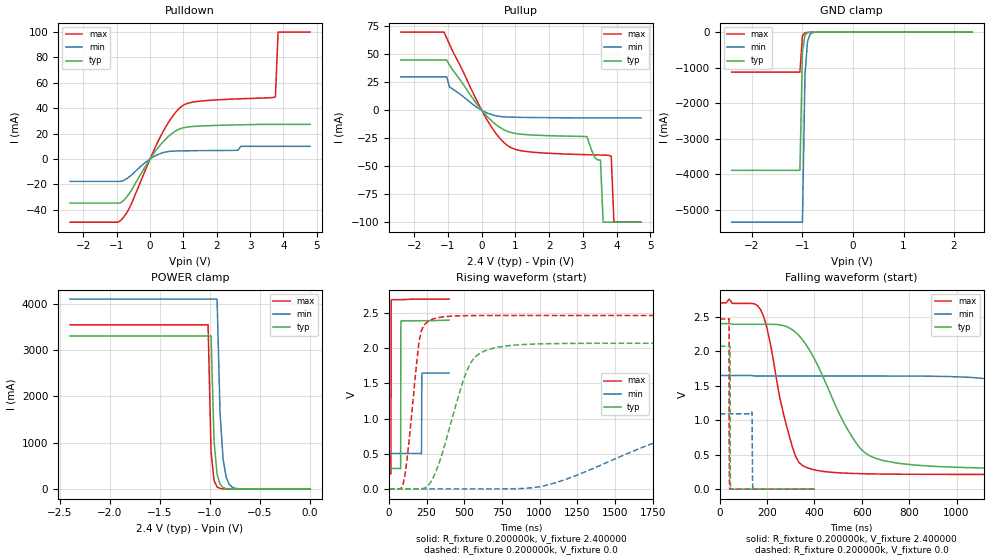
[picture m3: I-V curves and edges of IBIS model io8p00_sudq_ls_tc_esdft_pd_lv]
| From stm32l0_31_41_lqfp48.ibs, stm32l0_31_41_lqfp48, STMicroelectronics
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|   Model io8p00_sudq_ls_tc_esdft_pd_lv
[Model]  io8p00_sudq_ls_tc_esdft_pd_lv
Model_type I/O
Polarity   Non-Inverting
Enable   Active-Low
Vinl =   0.720000V
Vinh =   1.680000V
Vmeas =  1.200000V
Cref =   50.000000pF
Rref =   100.000000M
Vref =   0.0V
C_comp   2.242700pF   2.201100pF   2.288600pF
[Temperature Range]   25.000000   0.105000k   -40.000000
[Pullup Reference]   2.400000V   1.650000V   2.700000V
[Pulldown Reference]   0.0V   0.0V   0.0V
[POWER Clamp Reference]   2.400000V   1.650000V   2.700000V
[GND Clamp Reference]   0.0V   0.0V   0.0V
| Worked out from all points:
|   slope of the pulldown table from 0 to 0.36 V, typ, clamps not added: 28.4 ohm
|   slope of the pullup table from 0 to 0.36 V, typ, clamps not added: 32.2 ohm
|   GND clamp passes 1 mA (typ) near -0.64 V on its own axis
|   POWER clamp passes 1 mA (typ) near -0.63 V on its own axis
|   rising waveform, R_fixture 0.200000k, V_fixture 2.400000: 20-80 % time 636ps typ, 853ps min, 665ps max; typ from 0.29 V to 2.4 V
|   rising waveform, R_fixture 0.200000k, V_fixture 0.0: 20-80 % time 173ns typ, 835ns min, 69.6ns max; typ from 0 V to 2.07 V
|   falling waveform, R_fixture 0.200000k, V_fixture 2.400000: 20-80 % time 182ns typ, 740ns min, 90.7ns max; typ from 2.4 V to 0.29 V
|   falling waveform, R_fixture 0.200000k, V_fixture 0.0: 20-80 % time 751ps typ, 1.17ns min, 663ps max; typ from 2.07 V to 0 V
[Pulldown]
|Voltage   I(typ)   I(min)   I(max)
-2.4V     -34.71mA   -17.61mA   -49.77mA
-880mV    -34.55mA   -17.61mA   -48.41mA
-560mV    -24.66mA   -12.69mA   -35.31mA
240mV     8.893mA    3.542mA    13.9mA
560mV     17.98mA    5.931mA    29.16mA
880mV     23.58mA    6.388mA    40.03mA
1.44V     25.89mA    6.593mA    45.41mA
2.64V     26.92mA    7mA        47.38mA
2.72V     26.96mA    10mA       47.46mA
3.76V     27.3mA     10mA       49mA
3.84V     27.3mA     10mA       100mA
4.8V      27.3mA     10mA       100mA
[Pullup]
|Voltage   I(typ)   I(min)   I(max)
-2.4V     45mA       30mA       70mA
-1.12V    45mA       30mA       70mA
-960mV    40.7mA     21mA       59.3mA
80mV      -2.838mA   -1.261mA   -4.478mA
800mV     -19.21mA   -5.978mA   -32.18mA
3.12V     -23.45mA   -6.7mA     -39.62mA
3.36V     -42.52mA   -6.7mA     -39.81mA
3.52V     -44.4mA    -6.7mA     -39.93mA
3.6V      -100mA     -6.7mA     -40mA
3.84V     -100mA     -6.7mA     -41mA
3.92V     -100mA     -6.7mA     -100mA
4.72V     -100mA     -6.7mA     -100mA
[GND_clamp]
|Voltage   I(typ)   I(min)   I(max)
-2.4V     -3.892A    -5.353A    -1.127A
-1.05V    -3.892A    -5.353A    -1.127A
-1V       -568.8mA   -5.353A    -105.4mA
-950mV    -88.96mA   -1.19A     -18.04mA
-900mV    -18.16mA   -269.2mA   -8.968mA
-850mV    -6.712mA   -63.46mA   -6.577mA
-800mV    -4.026mA   -16.62mA   -4.866mA
-650mV    -1.055mA   -1.234mA   -1.154mA
2.35V     53.38uA    50.3uA     37.53uA
[POWER_clamp]
|Voltage   I(typ)   I(min)   I(max)
-2.4V     3.303A     4.097A     3.542A
-1.02V    3.303A     4.097A     3.542A
-990mV    3.303A     4.097A     802.4mA
-960mV    1.032A     4.097A     186.5mA
-930mV    325.2mA    4.097A     47.59mA
-900mV    104.8mA    1.637A     15.78mA
-870mV    35.83mA    655.7mA    8.015mA
-840mV    13.93mA    263.9mA    5.668mA
-810mV    6.712mA    107.2mA    4.56mA
-780mV    4.088mA    44.39mA    3.763mA
-690mV    1.741mA    4.361mA    1.91mA
0V        0A         0A         0A
[Ramp]
| variable   typ   min   max
dV/dt_r  0.65004/0.30835u   0.18965/0.83377u   1.03746/0.14880u
dV/dt_f  0.75702/0.32605u   0.19722/0.85428u   1.13766/0.16127u
R_load = 50.000000
[Rising Waveform]
R_fixture= 0.200000k
V_fixture= 2.400000
V_fixture_min= 1.650000
V_fixture_max= 2.700000
|time   V(typ)   V(min)   V(max)
0s        290.5mV    505.1mV    212.9mV
14.01ns   290.5mV    505.1mV    220.6mV
15.22ns   290.5mV    505.1mV    2.505V
16.82ns   290.5mV    505.1mV    2.688V
77.68ns   288.6mV    505.1mV    2.691V
79.28ns   2.143V     505.1mV    2.691V
80.88ns   2.387V     505.1mV    2.691V
215.8ns   2.391V     496.9mV    2.699V
220.2ns   2.391V     1.644V     2.699V
400ns     2.399V     1.648V     2.699V
[Rising Waveform]
R_fixture= 0.200000k
V_fixture= 0.0
V_fixture_min= 0.0
V_fixture_max= 0.0
|time   V(typ)   V(min)   V(max)
0s        1.516nV    9.763nV    1.154nV
93.43ns   -80.88uV   9.763nV    57.26mV
213.5ns   3.802mV    -11.57uV   2.232V
293.6ns   157.9mV    -17.79uV   2.416V
400.4ns   852.9mV    -17.64uV   2.454V
573.9ns   1.879V     13.42uV    2.465V
894.2ns   2.053V     7.836mV    2.466V
2.122us   2.071V     880mV      2.466V
2.976us   2.071V     1.062V     2.466V
13.33us   2.071V     1.091V     2.466V
[Falling Waveform]
R_fixture= 0.200000k
V_fixture= 2.400000
V_fixture_min= 1.650000
V_fixture_max= 2.700000
|time   V(typ)   V(min)   V(max)
0s        2.399V     1.648V     2.699V
173.5ns   2.389V     1.64V      2.597V
320.3ns   2.275V     1.64V      476.2mV
507.2ns   1.076V     1.64V      236.5mV
627.3ns   495.3mV    1.64V      222.1mV
827.5ns   348.1mV    1.639V     215.4mV
1.348us   297.2mV    1.496V     213mV
2.229us   290.7mV    711.5mV    212.9mV
3.016us   290.5mV    546.7mV    213mV
13.33us   290.5mV    505.1mV    212.9mV
[Falling Waveform]
R_fixture= 0.200000k
V_fixture= 0.0
V_fixture_min= 0.0
V_fixture_max= 0.0
|time   V(typ)   V(min)   V(max)
0s        2.071V     1.091V     2.466V
39.24ns   2.071V     1.091V     2.47V
40.44ns   2.071V     1.091V     422.3mV
42.84ns   2.071V     1.091V     2.944mV
43.64ns   2.07V      1.091V     694.5uV
45.25ns   157.4mV    1.091V     201.1uV
47.25ns   3.578mV    1.091V     162uV
136.5ns   16.97uV    1.116V     129.2uV
140.9ns   17.24uV    2.28mV     128.5uV
400ns     1.516nV    9.763nV    1.154nV
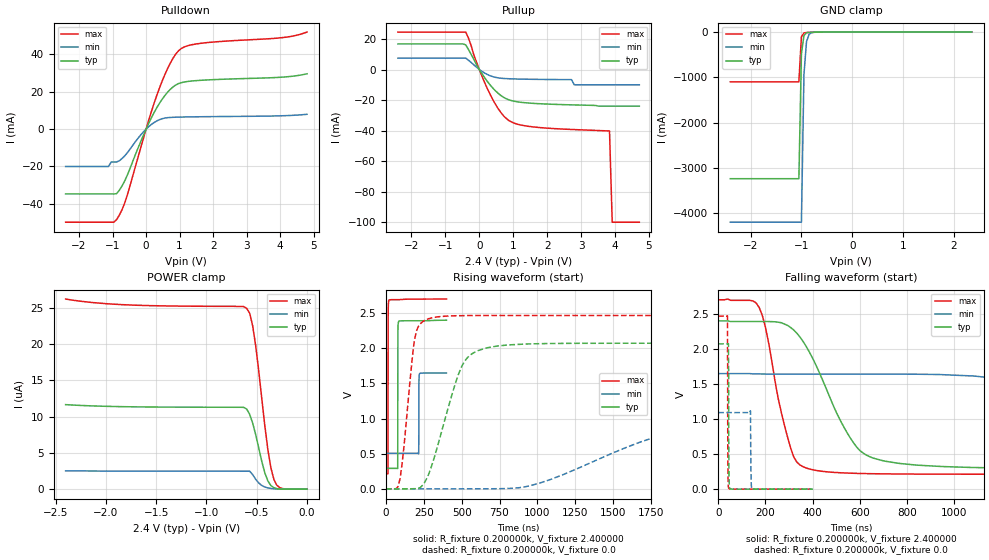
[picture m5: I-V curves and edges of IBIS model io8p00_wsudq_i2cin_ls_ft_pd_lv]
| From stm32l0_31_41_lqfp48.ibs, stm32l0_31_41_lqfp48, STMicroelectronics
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|   Model io8p00_wsudq_i2cin_ls_ft_pd_lv
[Model]  io8p00_wsudq_i2cin_ls_ft_pd_lv
Model_type I/O
Polarity   Non-Inverting
Enable   Active-Low
Vinl =   0.720000V
Vinh =   1.680000V
Vmeas =  1.200000V
Cref =   50.000000pF
Rref =   100.000000M
Vref =   0.0V
C_comp   2.943600pF   2.919700pF   2.965100pF
[Temperature Range]   25.000000   0.105000k   -40.000000
[Pullup Reference]   2.400000V   1.650000V   2.700000V
[Pulldown Reference]   0.0V   0.0V   0.0V
[POWER Clamp Reference]   2.400000V   1.650000V   2.700000V
[GND Clamp Reference]   0.0V   0.0V   0.0V
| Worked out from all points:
|   slope of the pulldown table from 0 to 0.36 V, typ, clamps not added: 28.5 ohm
|   slope of the pullup table from 0 to 0.36 V, typ, clamps not added: 32.2 ohm
|   GND clamp passes 1 mA (typ) near -0.64 V on its own axis
|   rising waveform, R_fixture 0.200000k, V_fixture 2.400000: 20-80 % time 682ps typ, 840ps min, 768ps max; typ from 0.291 V to 2.4 V
|   rising waveform, R_fixture 0.200000k, V_fixture 0.0: 20-80 % time 169ns typ, 821ns min, 66.4ns max; typ from 0 V to 2.07 V
|   falling waveform, R_fixture 0.200000k, V_fixture 2.400000: 20-80 % time 181ns typ, 729ns min, 89.8ns max; typ from 2.4 V to 0.291 V
|   falling waveform, R_fixture 0.200000k, V_fixture 0.0: 20-80 % time 1.21ns typ, 1.75ns min, 1.04ns max; typ from 2.07 V to 0 V
[Pulldown]
|Voltage   I(typ)   I(min)   I(max)
-2.4V     -34.7mA    -20mA      -49.82mA
-1.12V    -34.7mA    -20mA      -49.82mA
-1.04V    -34.7mA    -17.6mA    -49.82mA
-880mV    -34.55mA   -17.6mA    -48.46mA
-560mV    -24.65mA   -12.68mA   -35.33mA
0V        326fA      0A         140fA
400mV     13.84mA    5.066mA    22.03mA
720mV     21.25mA    6.254mA    35.26mA
1.04V     24.83mA    6.464mA    43.03mA
1.6V      26.11mA    6.627mA    45.88mA
4V        27.76mA    7.125mA    48.88mA
4.8V      29.63mA    7.94mA     51.96mA
[Pullup]
|Voltage   I(typ)   I(min)   I(max)
-2.4V     16.75mA    7.419mA    24.5mA
-400mV    16.1mA     7.419mA    24.5mA
0V        0A         0A         0A
320mV     -10.16mA   -4.078mA   -16.34mA
640mV     -17.08mA   -5.718mA   -28.28mA
960mV     -20.45mA   -6.128mA   -34.5mA
1.76V     -22.39mA   -6.47mA    -37.97mA
2.72V     -23.16mA   -6.63mA    -39.27mA
2.8V      -23.2mA    -10mA      -39.35mA
3.84V     -24mA      -10mA      -40.2mA
3.92V     -24mA      -10mA      -100mA
4.72V     -24mA      -10mA      -100mA
[GND_clamp]
|Voltage   I(typ)   I(min)   I(max)
-2.4V     -3.237A    -4.198A    -1.1A
-1.05V    -3.237A    -4.198A    -1.1A
-1V       -475.8mA   -4.198A    -104.2mA
-950mV    -76.26mA   -935.5mA   -18.4mA
-900mV    -16.62mA   -212.9mA   -9.114mA
-850mV    -6.559mA   -50.96mA   -6.598mA
-800mV    -4.01mA    -13.82mA   -4.868mA
-650mV    -1.055mA   -1.198mA   -1.154mA
2.35V     52.69uA    50.02uA    36.84uA
[POWER_clamp]
|Voltage   I(typ)   I(min)   I(max)
-2.4V     11.64uA    2.525uA    26.17uA
-1.86V    11.37uA    2.488uA    25.42uA
-600mV    11.04uA    2.474uA    24.9uA
-570mV    10.3uA     2.473uA    24.21uA
-540mV    9.097uA    2uA        22.48uA
-510mV    7.497uA    1.35uA     19.73uA
-450mV    3.845uA    512.5nA    12.52uA
-390mV    1.154uA    175.5nA    5.528uA
-360mV    508.2nA    102.8nA    2.997uA
-330mV    204.4nA    60.39nA    1.375uA
-270mV    0A         0A         194.9nA
0V        0A         0A         0A
[Ramp]
| variable   typ   min   max
dV/dt_r  0.65004/0.30141u   0.18965/0.80878u   1.03746/0.14367u
dV/dt_f  0.75702/0.32175u   0.19716/0.84592u   1.13800/0.15990u
R_load = 50.000000
[Rising Waveform]
R_fixture= 0.200000k
V_fixture= 2.400000
V_fixture_min= 1.650000
V_fixture_max= 2.700000
|time   V(typ)   V(min)   V(max)
0s        290.6mV    505.5mV    212.8mV
14.01ns   290.6mV    505.5mV    219.7mV
15.22ns   290.6mV    505.5mV    2.409V
19.22ns   290.6mV    505.5mV    2.678V
77.68ns   288.8mV    505.5mV    2.691V
79.68ns   2.247V     505.5mV    2.691V
84.48ns   2.379V     505.5mV    2.691V
216.2ns   2.391V     500.8mV    2.699V
222.2ns   2.391V     1.637V     2.699V
400ns     2.399V     1.648V     2.699V
[Rising Waveform]
R_fixture= 0.200000k
V_fixture= 0.0
V_fixture_min= 0.0
V_fixture_max= 0.0
|time   V(typ)   V(min)   V(max)
0s        2.005nV    12.66nV    1.54nV
93.43ns   -110uV     12.66nV    141.3mV
200.2ns   2.435mV    12.66nV    2.236V
280.3ns   197.1mV    -23.14uV   2.418V
360.4ns   756.5mV    -23.14uV   2.45V
547.2ns   1.885V     110.9uV    2.464V
934.3ns   2.061V     36.22mV    2.466V
1.949us   2.071V     843.8mV    2.466V
2.723us   2.071V     1.05V      2.466V
13.33us   2.071V     1.091V     2.466V
[Falling Waveform]
R_fixture= 0.200000k
V_fixture= 2.400000
V_fixture_min= 1.650000
V_fixture_max= 2.700000
|time   V(typ)   V(min)   V(max)
0s        2.399V     1.648V     2.699V
173.5ns   2.389V     1.642V     2.59V
320.3ns   2.267V     1.64V      455.5mV
520.5ns   958.3mV    1.64V      233.1mV
627.3ns   484.9mV    1.64V      221.9mV
840.8ns   342.9mV    1.638V     214.9mV
1.335us   297.2mV    1.497V     212.9mV
2.189us   290.8mV    722mV      212.8mV
2.816us   290.6mV    562.9mV    212.8mV
13.33us   290.6mV    505.5mV    212.8mV
[Falling Waveform]
R_fixture= 0.200000k
V_fixture= 0.0
V_fixture_min= 0.0
V_fixture_max= 0.0
|time   V(typ)   V(min)   V(max)
0s        2.071V     1.091V     2.466V
39.24ns   2.071V     1.091V     2.47V
41.24ns   2.071V     1.091V     281.2mV
43.64ns   2.07V      1.091V     24.64mV
44.84ns   697.4mV    1.091V     12.09mV
48.85ns   14.19mV    1.091V     2.613mV
136.5ns   20.59uV    1.117V     136.5uV
139.3ns   20.66uV    152mV      136.9uV
143.3ns   20.76uV    6.515mV    137.4uV
400ns     2.005nV    12.66nV    1.54nV
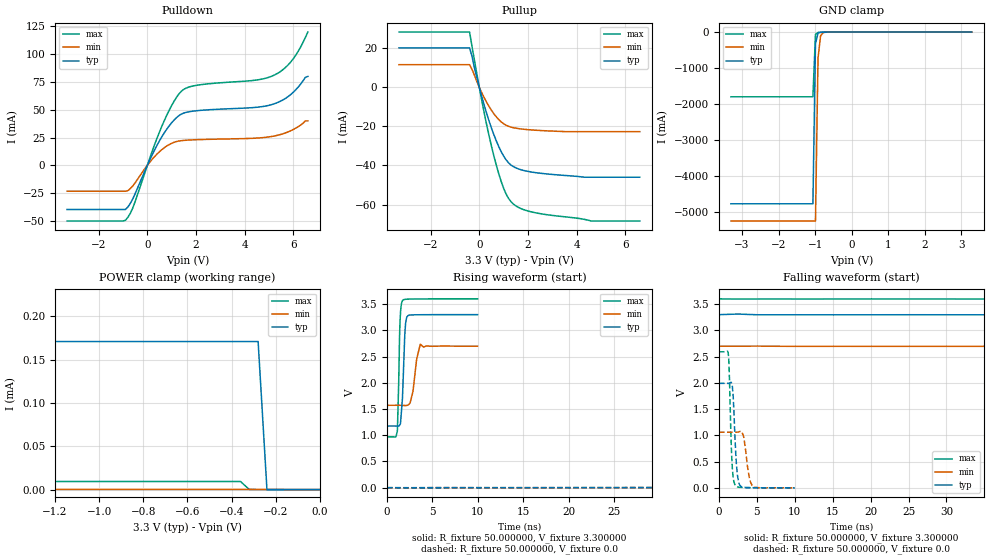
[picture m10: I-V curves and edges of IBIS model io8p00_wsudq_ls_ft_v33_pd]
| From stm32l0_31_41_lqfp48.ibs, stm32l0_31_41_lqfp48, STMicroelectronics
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|   Model io8p00_wsudq_ls_ft_v33_pd
[Model]  io8p00_wsudq_ls_ft_v33_pd
Model_type I/O
Polarity   Non-Inverting
Enable   Active-Low
Vinl =   0.990000V
Vinh =   2.310000V
Vmeas =  1.650000V
Cref =   50.000000pF
Rref =   100.000000M
Vref =   0.0V
C_comp   2.653200pF   2.620200pF   2.695100pF
[Temperature Range]   25.000000   0.125000k   -40.000000
[Pullup Reference]   3.300000V   2.700000V   3.600000V
[Pulldown Reference]   0.0V   0.0V   0.0V
[POWER Clamp Reference]   3.300000V   2.700000V   3.600000V
[GND Clamp Reference]   0.0V   0.0V   0.0V
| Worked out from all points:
|   slope of the pulldown table from 0 to 0.495 V, typ, clamps not added: 22.6 ohm
|   slope of the pullup table from 0 to 0.495 V, typ, clamps not added: 23.9 ohm
|   GND clamp passes 1 mA (typ) near -0.64 V on its own axis
|   POWER clamp passes 1 mA (typ) near -2.99 V on its own axis
|   rising waveform, R_fixture 50.000000, V_fixture 3.300000: 20-80 % time 295ps typ, 497ps min, 208ps max; typ from 1.18 V to 3.3 V
|   rising waveform, R_fixture 50.000000, V_fixture 0.0: 20-80 % time 206ns typ, 424ns min, 99.3ns max; typ from 0 V to 1.99 V
|   falling waveform, R_fixture 50.000000, V_fixture 3.300000: 20-80 % time 198ns typ, 393ns min, 106ns max; typ from 3.3 V to 1.18 V
|   falling waveform, R_fixture 50.000000, V_fixture 0.0: 20-80 % time 408ps typ, 593ps min, 324ps max; typ from 1.99 V to 0 V
[Pulldown]
|Voltage   I(typ)   I(min)   I(max)
-3.3V     -39.83mA   -23.36mA   -50.2mA
-900mV    -39.83mA   -23.36mA   -49.53mA
-600mV    -30.28mA   -18.58mA   -38.45mA
500mV     22.11mA    12.27mA    30.1mA
1V        38.33mA    19.81mA    53.88mA
1.4V      46.1mA     22.17mA    66.71mA
2V        49.06mA    23.01mA    71.93mA
4.4V      52.05mA    24.37mA    76.53mA
5.2V      55.25mA    26.3mA     81.02mA
5.9V      63.82mA    31.15mA    93.17mA
6.2V      70.38mA    34.74mA    102.5mA
6.6V      80mA       40mA       120mA
[Pullup]
|Voltage   I(typ)   I(min)   I(max)
-3.3V     20.14mA    11.53mA    28.22mA
-400mV    20.14mA    11.53mA    28.22mA
100mV     -4.683mA   -2.741mA   -6.645mA
400mV     -17.2mA    -9.8mA     -24.68mA
600mV     -24.27mA   -13.54mA   -35.11mA
800mV     -30.3mA    -16.51mA   -44.18mA
1V        -35.17mA   -18.65mA   -51.61mA
1.2V      -38.59mA   -19.95mA   -56.76mA
1.4V      -40.56mA   -20.67mA   -59.68mA
2.2V      -43.44mA   -21.87mA   -63.88mA
4.6V      -46mA      -22.71mA   -68.38mA
6.6V      -46mA      -22.71mA   -68.38mA
[GND_clamp]
|Voltage   I(typ)   I(min)   I(max)
-3.3V     -4.766A    -5.244A    -1.797A
-1.06V    -4.766A    -5.244A    -1.797A
-990mV    -326.8mA   -5.244A    -68.06mA
-920mV    -29.1mA    -722.2mA   -11.17mA
-850mV    -6.81mA    -104.4mA   -6.691mA
-780mV    -3.567mA   -17.46mA   -4.273mA
-500mV    -68.7uA    -184.5uA   -41.56uA
3.28V     73.95uA    88.62uA    51.48uA
[POWER_clamp]
|Voltage   I(typ)   I(min)   I(max)
-3.28V    3.05A      15.65uA    3.723A
-3.2V     3.05A      1.687uA    3.723A
-2.96V    269.4uA    209.1nA    3.723A
-2.92V    170.9uA    209.1nA    508.5mA
-2.8V     170.9uA    209.1nA    1.296mA
-2.76V    170.9uA    209.1nA    177.1uA
-2.72V    170.9uA    209.1nA    24.25uA
-2.68V    170.9uA    209.1nA    9.362uA
-360mV    170.9uA    209.1nA    9.362uA
-280mV    170.9uA    209.1nA    0A
-240mV    0A         209.1nA    0A
0V        0A         0A         0A
[Ramp]
| variable   typ   min   max
dV/dt_r  1.19430/0.20576u   0.61380/0.43186u   1.55532/99.23574n
dV/dt_f  1.27290/0.19842u   0.63702/0.40471u   1.57834/0.10606u
R_load = 50.000000
[Rising Waveform]
R_fixture= 50.000000
V_fixture= 3.300000
V_fixture_min= 2.700000
V_fixture_max= 3.600000
|time   V(typ)   V(min)   V(max)
0s        1.176V     1.571V     968.8mV
1.141ns   1.173V     1.571V     1.081V
1.421ns   1.203V     1.571V     3.097V
1.702ns   1.703V     1.569V     3.562V
1.982ns   2.976V     1.566V     3.59V
2.282ns   3.275V     1.574V     3.594V
2.863ns   3.294V     1.838V     3.596V
3.263ns   3.296V     2.446V     3.598V
3.664ns   3.297V     2.736V     3.598V
9.97ns    3.299V     2.698V     3.599V
[Rising Waveform]
R_fixture= 50.000000
V_fixture= 0.0
V_fixture_min= 0.0
V_fixture_max= 0.0
|time   V(typ)   V(min)   V(max)
0s        2.232nV    16.52nV    4.706nV
37.54ns   -71.75uV   -697.1uV   10.72mV
72.57ns   36.59mV    714.5uV    419.6mV
105.1ns   101.7mV    257.6uV    1.015V
157.7ns   417.5mV    9.224mV    1.852V
230.2ns   923.7mV    53.39mV    2.418V
355.4ns   1.576V     190mV      2.569V
498ns     1.873V     432.6mV    2.59V
815.8ns   1.984V     873.8mV    2.592V
1.246us   1.99V      1.06V      2.592V
[Falling Waveform]
R_fixture= 50.000000
V_fixture= 3.300000
V_fixture_min= 2.700000
V_fixture_max= 3.600000
|time   V(typ)   V(min)   V(max)
0s        3.299V     2.698V     3.599V
72.57ns   3.296V     2.695V     3.546V
122.6ns   3.26V      2.695V     2.911V
212.7ns   2.806V     2.691V     1.555V
245.2ns   2.589V     2.67V      1.24V
277.8ns   2.363V     2.644V     1.095V
382.9ns   1.669V     2.55V      1.002V
515.5ns   1.308V     2.321V     979.3mV
865.9ns   1.19V      1.744V     969.1mV
1.246us   1.176V     1.571V     968.8mV
[Falling Waveform]
R_fixture= 50.000000
V_fixture= 0.0
V_fixture_min= 0.0
V_fixture_max= 0.0
|time   V(typ)   V(min)   V(max)
0s        1.99V      1.06V      2.592V
1.221ns   1.99V      1.06V      2.575V
1.321ns   1.991V     1.06V      2.373V
1.702ns   1.978V     1.06V      556.2mV
1.882ns   1.744V     1.06V      198mV
2.122ns   940.9mV    1.06V      58.22mV
2.442ns   243.5mV    1.061V     17.97mV
2.883ns   30.29mV    1.076V     8.934mV
4.404ns   3.343mV    40.93mV    1.581mV
9.97ns    2.232nV    16.52nV    4.706nV
